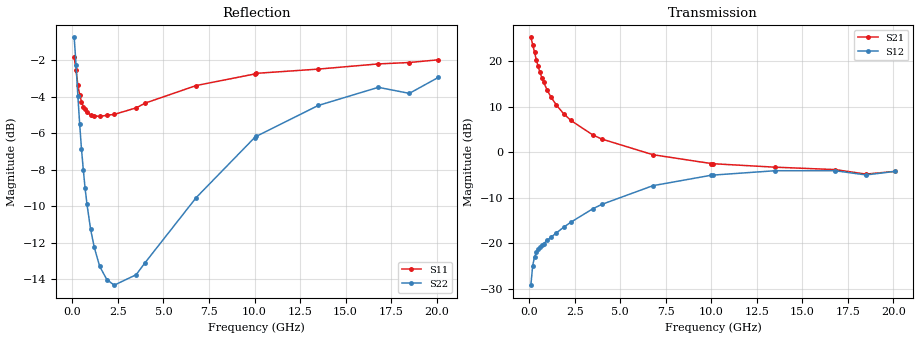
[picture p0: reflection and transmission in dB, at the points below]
!  Infineon Technologies AG
! BFR380L3 , PF131585-7, No.6, Th 09.10.01, soldered on pcb-board, measured with PP GSG850
!  Vce=1.0 V,  Ic=6.0 mA
! Common Emitter S-Parameters:  15. November 2001
#  GHz  S  MA  R  50
! f  S11  S21  S12  S22
! GHz  Mag  Ang  Mag  Ang  Mag  Ang  Mag  Ang
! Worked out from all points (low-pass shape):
!   201 points, 100 MHz to 20.1 GHz, reference 50 ohm
!   highest |S21| = 25.25 dB at 100 MHz (marker M1); lowest = -4.8 dB at 18.5 GHz (marker M2)
!   |S21| within 3 dB of the highest: start of sweep to 283.4 MHz
!   lowest |S11| = -5.1 dB at 1.5 GHz (marker M3), VSWR 3.52, Z = 14.2 - j1.36 ohm
!   |S11| at or under -10 dB: nowhere
!   |S22| runs from -14.3 to -0.7 dB; largest |S21 - S12| = 18
!   S11 on the Smith chart (normalised r, x): 100 MHz: 0.93, -2.68; 300 MHz: 0.36, -0.91; 1 GHz: 0.29, -0.18; 4 GHz: 0.28, +0.37; 10 GHz: 0.39, +1.17; 20.1 GHz: 0.95, +2.57
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0.1  0.8119 -37.3  18.3 156.4  0.03467 69.8  0.9176 -24.4
0.2  0.746 -68.1  15.28 138.0  0.0568 57.8  0.7726 -43.6
0.3  0.6812 -91.6  12.54 125.0  0.07089 49.7  0.6361 -57.2
0.4  0.6395 -108.7  10.4 115.6  0.07919 45.0  0.5316 -67.1
0.5  0.6115 -122.0  8.774 108.7  0.08542 42.7  0.4545 -74.8
0.6  0.5927 -132.1  7.553 103.3  0.09053 41.7  0.3978 -80.8
0.7  0.5825 -140.7  6.623 98.7  0.09483 41.4  0.3541 -86.0
0.8  0.5718 -147.4  5.879 94.9  0.09914 41.6  0.3209 -90.4
1  0.5633 -158.3  4.802 88.5  0.1076 42.5  0.2741 -98.0
1.2  0.5596 -166.8  4.056 83.2  0.1162 43.9  0.2444 -104.4
1.5  0.5574 -176.6  3.301 76.4  0.13 45.8  0.2166 -112.7
1.9  0.5617 172.8  2.654 68.6  0.1499 47.7  0.199 -122.4
2.3  0.5647 164.3  2.234 61.6  0.1707 48.7  0.1925 -131.0
3.5  0.5884 143.3  1.551 43.8  0.2393 48.1  0.2055 -151.3
4  0.6064 136.3  1.396 37.6  0.2677 46.6  0.222 -160.0
6.8  0.6774 103.2  0.9401 10.3  0.4293 31.6  0.3343 161.0
10  0.7283 77.6  0.7518 -8.1  0.559 10.8  0.4876 127.1
10.1  0.7315 77.1  0.7483 -8.3  0.5613 10.2  0.4918 126.0
13.5  0.7513 59.3  0.6857 -22.7  0.6265 -10.9  0.5974 96.9
16.8  0.7763 47.4  0.645 -34.0  0.6266 -26.8  0.6698 75.6
18.5  0.7831 45.3  0.5755 -41.4  0.5635 -35.2  0.6447 70.1
20.1  0.7968 38.2  0.6171 -44.6  0.6166 -40.2  0.7132 59.5
